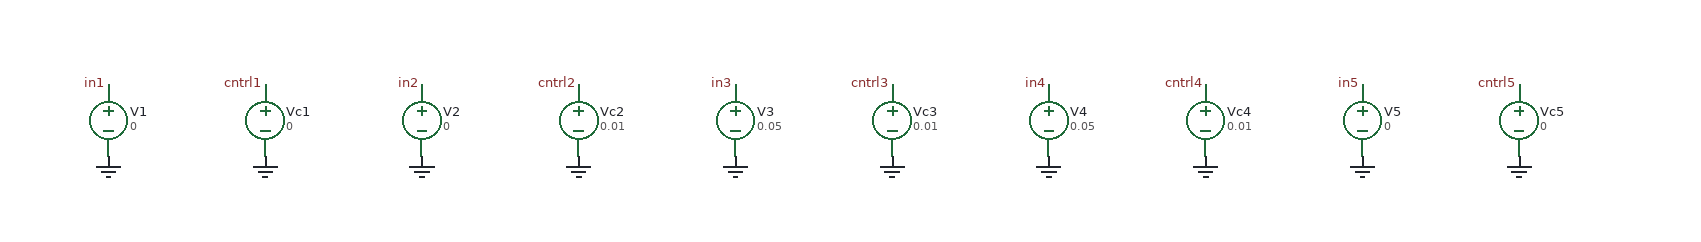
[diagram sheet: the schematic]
v {xschem version=3.4.5 file_version=1.2}
G {}
K {}
V {}
S {}
E {}
C {devices/vsource.sym} 300 150 0 0 {name=V1
value=0}
C {devices/vsource.sym} 430 150 0 0 {name=Vc1
value=0}
C {devices/vsource.sym} 560 150 0 0 {name=V2
value=0}
C {devices/vsource.sym} 690 150 0 0 {name=Vc2
value=0.01}
C {devices/vsource.sym} 820 150 0 0 {name=V3
value=0.05}
C {devices/vsource.sym} 950 150 0 0 {name=Vc3
value=0.01}
C {devices/vsource.sym} 1080 150 0 0 {name=V4
value=0.05}
C {devices/vsource.sym} 1210 150 0 0 {name=Vc4
value=0.01}
C {devices/vsource.sym} 1340 150 0 0 {name=V5
value=0}
C {devices/vsource.sym} 1470 150 0 0 {name=Vc5
value=0}
C {devices/lab_pin.sym} 300 120 0 0 {name=l_in1 sig_type=std_logic lab=in1}
C {devices/gnd.sym} 300 180 0 0 {name=l_0 lab=GND}
C {devices/gnd.sym} 430 180 0 0 {name=l_0 lab=GND}
C {devices/gnd.sym} 560 180 0 0 {name=l_0 lab=GND}
C {devices/gnd.sym} 690 180 0 0 {name=l_0 lab=GND}
C {devices/gnd.sym} 820 180 0 0 {name=l_0 lab=GND}
C {devices/gnd.sym} 950 180 0 0 {name=l_0 lab=GND}
C {devices/gnd.sym} 1080 180 0 0 {name=l_0 lab=GND}
C {devices/gnd.sym} 1210 180 0 0 {name=l_0 lab=GND}
C {devices/gnd.sym} 1340 180 0 0 {name=l_0 lab=GND}
C {devices/gnd.sym} 1470 180 0 0 {name=l_0 lab=GND}
C {devices/lab_pin.sym} 430 120 0 0 {name=l_cntrl1 sig_type=std_logic lab=cntrl1}
C {devices/lab_pin.sym} 560 120 0 0 {name=l_in2 sig_type=std_logic lab=in2}
C {devices/lab_pin.sym} 690 120 0 0 {name=l_cntrl2 sig_type=std_logic lab=cntrl2}
C {devices/lab_pin.sym} 820 120 0 0 {name=l_in3 sig_type=std_logic lab=in3}
C {devices/lab_pin.sym} 950 120 0 0 {name=l_cntrl3 sig_type=std_logic lab=cntrl3}
C {devices/lab_pin.sym} 1080 120 0 0 {name=l_in4 sig_type=std_logic lab=in4}
C {devices/lab_pin.sym} 1210 120 0 0 {name=l_cntrl4 sig_type=std_logic lab=cntrl4}
C {devices/lab_pin.sym} 1340 120 0 0 {name=l_in5 sig_type=std_logic lab=in5}
C {devices/lab_pin.sym} 1470 120 0 0 {name=l_cntrl5 sig_type=std_logic lab=cntrl5}
